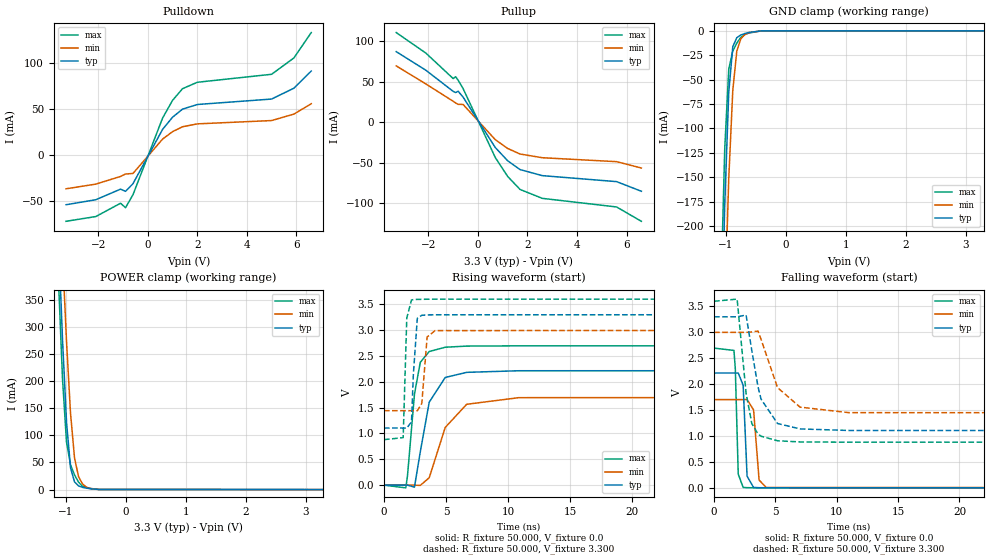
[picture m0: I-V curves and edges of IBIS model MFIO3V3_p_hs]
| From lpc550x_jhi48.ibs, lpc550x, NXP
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|   Model MFIO3V3_p_hs
[Model] MFIO3V3_p_hs
Model_type I/O
Polarity   Non-Inverting
Enable   Active-Low
Vinl =  0.990V
Vinh =  2.310V
Vmeas =  1.650V
Cref =  0.0F
Rref =  100.000
Vref =  0.0V
C_comp   1.925pF   1.906pF   1.947pF
C_comp_pullup   1.144pF   1.140pF   1.152pF
C_comp_pulldown   0.642pF   0.634pF   0.649pF
[Model Spec]
Vinh   2.310V   2.100V   2.520V
Vinl   0.990V   0.900V   1.080V
Vmeas   1.650V   1.500V   1.800V
Vref   0.0V   0.0V   0.0V
Cref   0.0F   0.0F   0.0F
Rref   100.000   100.000   100.000
[Temperature Range]   25.000   0.125k   -40.000
[Voltage Range]   3.300V   3.000V   3.600V
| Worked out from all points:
|   slope of the pulldown table from 0 to 0.495 V, typ, clamps not added: 20.7 ohm
|   slope of the pullup table from 0 to 0.495 V, typ, clamps not added: 21.4 ohm
|   GND clamp passes 1 mA (typ) near -0.56 V on its own axis
|   POWER clamp passes 1 mA (typ) near -0.54 V on its own axis
|   rising waveform, R_fixture 50.000, V_fixture 0.0: 20-80 % time 1.05ns typ, 1.66ns min, 670ps max; typ from 0 V to 2.21 V
|   rising waveform, R_fixture 50.000, V_fixture 3.300: 20-80 % time 177ps typ, 254ps min, 147ps max; typ from 1.1 V to 3.3 V
|   falling waveform, R_fixture 50.000, V_fixture 0.0: 20-80 % time 203ps typ, 291ps min, 162ps max; typ from 2.21 V to 0 V
|   falling waveform, R_fixture 50.000, V_fixture 3.300: 20-80 % time 1.14ns typ, 1.68ns min, 740ps max; typ from 3.3 V to 1.1 V
[Pulldown]
|Voltage   I(typ)   I(min)   I(max)
-3.3V     -53.7mA    -36.43mA   -71.67mA
-2.1V     -48.29mA   -31.37mA   -66.51mA
-1.1V     -36.82mA   -23.05mA   -52.1mA
-900mV    -39.2mA    -20.39mA   -56.91mA
-600mV    -30.96mA   -19.83mA   -42.97mA
600mV     28.07mA    17.5mA     40.4mA
1V        41.17mA    25.53mA    59.41mA
1.4V      49.87mA    30.79mA    72.04mA
2V        54.93mA    33.94mA    79.03mA
5V        60.84mA    37.53mA    87.68mA
5.9V      72.62mA    44.52mA    105.4mA
6.6V      91.19mA    55.78mA    132.9mA
[Pullup]
|Voltage   I(typ)   I(min)   I(max)
-3.3V     87.16mA    69.54mA    110.7mA
-2.1V     64.12mA    47.22mA    85.31mA
-1V       38.1mA     25.85mA    53.88mA
-900mV    36.64mA    23.75mA    56.16mA
-800mV    38.25mA    22.02mA    51.93mA
-600mV    31.06mA    21.93mA    41.58mA
700mV     -31.25mA   -21.55mA   -43.56mA
1.2V      -47.6mA    -32.42mA   -66.97mA
1.7V      -58.52mA   -39.3mA    -83.05mA
2.6V      -66.01mA   -43.88mA   -94.06mA
5.6V      -73.4mA    -48.74mA   -104.7mA
6.6V      -85.32mA   -56.6mA    -122.4mA
[GND_clamp]
|Voltage   I(typ)   I(min)   I(max)
-3.3V     -7.222A    -7.177A    -7.278A
-1.089V   -337.1mA   -440.8mA   -274.1mA
-1.022V   -178.2mA   -284.2mA   -121mA
-955mV    -63.04mA   -151.6mA   -39.24mA
-888mV    -16.32mA   -61.33mA   -20.89mA
-821mV    -7.057mA   -20.83mA   -12.64mA
-754mV    -4.256mA   -8.15mA    -6.682mA
-687mV    -2.785mA   -3.888mA   -3.83mA
-620mV    -1.717mA   -1.887mA   -2.329mA
-419mV    -104.8uA   -131.8uA   -126uA
3.3V      0A         0A         0A
[POWER_clamp]
|Voltage   I(typ)   I(min)   I(max)
-3.3V     8.016A     7.986A     8.074A
-1.122V   463.7mA    614.3mA    384.9mA
-1.055V   276.2mA    434.9mA    203.8mA
-988mV    124mA      272.3mA    87.12mA
-921mV    39.95mA    140.1mA    45.59mA
-854mV    14.16mA    57.77mA    27.02mA
-787mV    6.846mA    23.74mA    13.67mA
-720mV    4.066mA    10.21mA    6.113mA
-653mV    2.607mA    4.361mA    3.605mA
-586mV    1.542mA    1.86mA     2.097mA
-452mV    273.4uA    353.7uA    329.6uA
3.3V      0A         0A         0A
[Ramp]
| variable   typ   min   max
dV/dt_r   1.329/1.049n   1.022/1.660n   1.618/0.670n
dV/dt_f   1.317/1.134n   0.935/1.674n   1.632/0.744n
R_load = 50.000
[Rising Waveform]
R_fixture= 50.000
V_fixture= 0.0
V_fixture_min= 0.0
V_fixture_max= 0.0
|time   V(typ)   V(min)   V(max)
0s        11.91nV    127.2nV    48.18nV
1.76ns    14.07uV    -452.3nV   -52.48mV
1.9ns     130.3uV    -183.4nV   185.6mV
2.46ns    -38.99mV   68.8uV     1.761V
2.93ns    644.9mV    -5.155mV   2.378V
3.65ns    1.606V     144.1mV    2.586V
4.94ns    2.084V     1.117V     2.669V
6.67ns    2.183V     1.565V     2.691V
10.87ns   2.214V     1.693V     2.696V
100ns     2.215V     1.703V     2.696V
[Rising Waveform]
R_fixture= 50.000
V_fixture= 3.300
V_fixture_min= 3.000
V_fixture_max= 3.600
|time   V(typ)   V(min)   V(max)
0s        1.105V     1.441V     880.7mV
1.55ns    1.105V     1.441V     919.6mV
1.84ns    1.105V     1.441V     3.233V
2.22ns    1.224V     1.441V     3.584V
2.37ns    2.139V     1.441V     3.59V
2.69ns    3.23V      1.44V      3.595V
3.05ns    3.287V     1.579V     3.596V
3.48ns    3.294V     2.867V     3.598V
4.12ns    3.297V     2.991V     3.599V
100ns     3.3V       3V         3.6V
[Falling Waveform]
R_fixture= 50.000
V_fixture= 0.0
V_fixture_min= 0.0
V_fixture_max= 0.0
|time   V(typ)   V(min)   V(max)
0s        2.215V     1.703V     2.696V
1.62ns    2.215V     1.703V     2.651V
1.73ns    2.215V     1.703V     2.303V
1.97ns    2.215V     1.703V     265.7mV
2.37ns    1.981V     1.703V     8.251mV
2.69ns    225.2mV    1.704V     3.621mV
3.22ns    7.595mV    1.504V     1.863mV
3.67ns    3.256mV    150.5mV    1.23mV
4.25ns    1.815mV    7.854mV    743.4uV
100ns     16.41nV    135.3nV    50.94nV
[Falling Waveform]
R_fixture= 50.000
V_fixture= 3.300
V_fixture_min= 3.000
V_fixture_max= 3.600
|time   V(typ)   V(min)   V(max)
0s        3.3V       3V         3.6V
1.88ns    3.3V       3V         3.641V
2.61ns    3.334V     3V         1.821V
3.08ns    2.642V     3.008V     1.24V
3.58ns    1.951V     3.025V     1.041V
3.83ns    1.711V     2.865V     995.8mV
5.17ns    1.242V     1.934V     908.5mV
7.01ns    1.137V     1.557V     886.1mV
10.99ns   1.107V     1.451V     880.9mV
100ns     1.105V     1.441V     880.7mV
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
